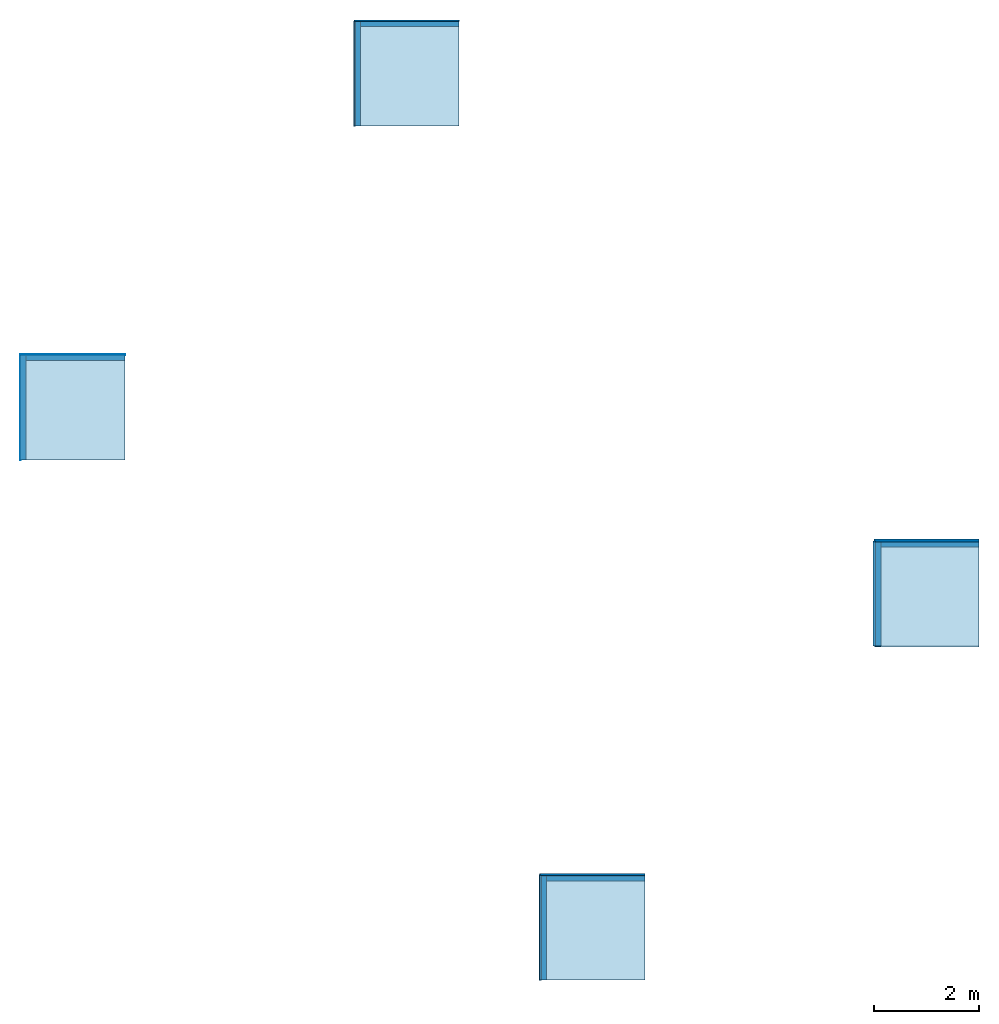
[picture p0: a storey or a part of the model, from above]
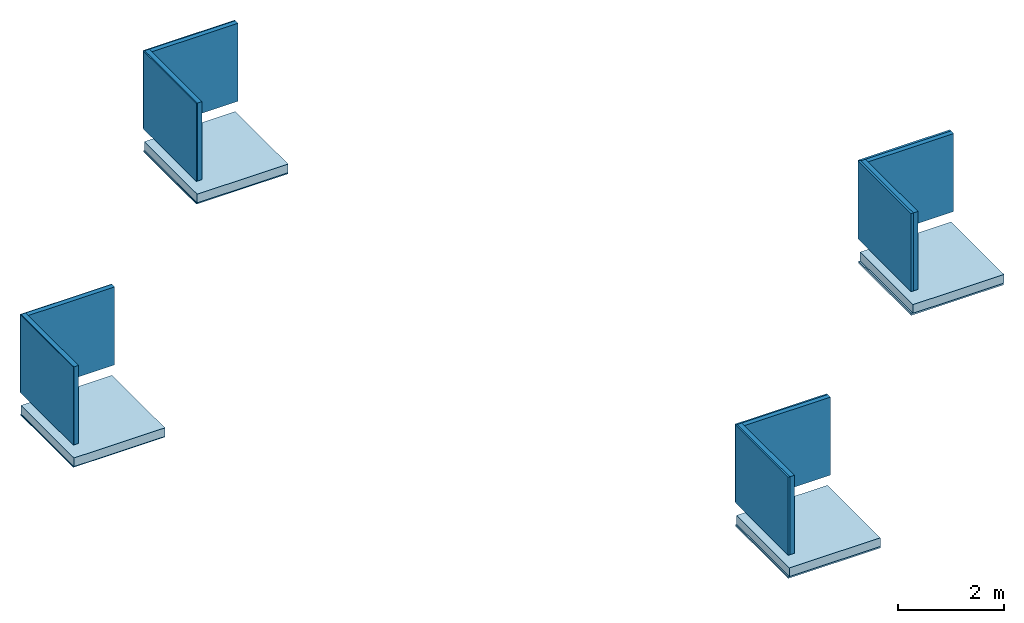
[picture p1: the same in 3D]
Properties of the parts of a building model (IFC2X3)

# File
Description: ViewDefinition [CoordinationView_V2.0, QuantityTakeOffAddOnView]
File name: 012345
Time: 2019-12-04T12:57:39
Written by: The EXPRESS Data Manager Version 5.02.0100.07 : 28 Aug 2013
Made in: 20190507_1515(x64) - Exporter 17.0.517.0 - Alternate UI 17.15.0.0
Comment: STEP Physical File produced by: The EXPRESS Data Manager Version 5.02.0100.07 : 28 Aug 2013 * Module: EDMstepFileFactory/EDMstandAlone * Creation date: Wed Dec 04 12:57:39 2019 * Host: lt-026 * Database: C:\Users\WF2BF~1.POE\AppData\Local\Temp\{160A05C8-261A-411D-A7B8-0925D6DDFBA5}\ifc * Database version: 5507 * Database creation date: Wed Dec 04 12:57:36 2019 * Schema: IFC2X3 * Model: DataRepository.ifc * Model creation date: Wed Dec 04 12:57:37 2019 * Header model: DataRepository.ifc_HeaderModel * Header model creation date: Wed Dec 04 12:57:37 2019 * EDMuser: sdai-user * EDMgroup: sdai-group * License ID and type: 5605 : Permanent license. Expiry date: * EDMstepFileFactory options: 020000

# IfcProject, 012345
LongName: Cadix Project Naam; Phase: Cadix leeg V2.0

# IfcSite, Default
RefLatitude: 52, 3, 20, 225830; RefLongitude: 5, 6, 28, 692855; RefElevation: 0 mm
Identity Data - Author: Cadix; Organization Name: Cadix
Other - Category: Project Information; Client Name: Vragen? info@cadix.nl; Project Address: Ampèrelaan 1c, 9207 AM Drachten; Project Issue Date: 06-06-2017; Project Name: Cadix Project Naam; Project Number: 012345; Project Status: Cadix leeg V2.0

# IfcBuilding
Pset_BuildingCommon - NumberOfStoreys: 2
Identity Data - Author: Cadix; Organization Name: Cadix
Other - Category: Project Information; Client Name: Vragen? info@cadix.nl; Project Address: Ampèrelaan 1c, 9207 AM Drachten; Project Issue Date: 06-06-2017; Project Name: Cadix Project Naam; Project Number: 012345; Project Status: Cadix leeg V2.0

# IfcBuildingStorey (2)
Dimensions - Computation Height: 0 mm
Identity Data - Structural: no; Building Story: yes; Type Name: niveau
Other - Category: Levels; Family: Level: niveau; Family and Type: Level: niveau; Type: Level: niveau; Type Id: Level: niveau; Family Name: Level
Constraints - Elevation Base: Project Base Point
Graphics - Color: 8421504; Line Pattern: 00_niveau; Line Weight: 1; Symbol: NLRS_00_LAB_niveau bovenkant_gen_cadix: 1.8mm; Symbol at End 1 Default: yes; Symbol at End 2 Default: no
Name | LongName = Name | Elevation (mm) | Constraints, Elevation (mm)
00 begane grond | 00 begane grond | -2.7707e-11 | 0
01 eerste verdieping | 01 eerste verdieping | 1800 | 1800

# IfcCovering: Compound Ceiling:NLRS_45_CEI_Heraklith - Basis 15x2000x600mm, Compound Ceiling:NLRS_45_CEI_Heraklith - Basis 15x2000x600mm:902306
In: 01 eerste verdieping
PredefinedType: CEILING; Classification: 45.0 (Uniformat); Material: Heraklith® | Basis - Houtwollaag - 2000x600mm 15 mm
Pset_CoveringCommon - Reference: NLRS_45_CEI_Heraklith - Basis 15x2000x600mm; Finish: Heraklith® | Basis - Houtwollaag - 2000x600mm;; TotalThickness: 15 mm
Pset_ManufacturerTypeInformation - Manufacturer: Knauf Insulation B.V.
BaseQuantities - GrossCeilingArea: 4 m2
Constraints - Height Offset From Level: -15 mm; Level: Level: 01 eerste verdieping; Room Bounding: yes
Dimensions - Area: 4 m2; Perimeter: 8000 mm; Volume: 0.06 m3
Other - Category: Ceilings; Family: Compound Ceiling: NLRS_45_CEI_Heraklith - Basis 15x2000x600mm; Family and Type: Compound Ceiling: NLRS_45_CEI_Heraklith - Basis 15x2000x600mm; Type: Compound Ceiling: NLRS_45_CEI_Heraklith - Basis 15x2000x600mm; Type Id: Compound Ceiling: NLRS_45_CEI_Heraklith - Basis 15x2000x600mm; Family Name: Compound Ceiling
Phasing - Phase Created: 1
Analytical Properties - Absorptance: 0.1; Heat Transfer Coefficient (U): 5.33333; Roughness: 1; Thermal mass: 675; Thermal Resistance (R): 0.1875
Construction - Thickness: 15 mm
Data - CE-codering: WW-EN 13168-L1-W1-T1-S1-P1-CS(10/Y)150/200-Cl1; Chloride gehalte: Cl1; Druksterkte kPa: 200; gewicht KG/M2: 8.5; kleur: Ongeverfd; pallet m2: 84 m2; panelen per pallet: 70; Randafwerking: Houtwol: Rechte kanten; Randafwerking: Isolatie: n.v.t.; Tolerantie: Breedte (W): (W1) +3/-3; Tolerantie: Dikte (T): (T1) +3/-2; Tolerantie: Haaksheid (S): (S1) ≤4; Tolerantie: Lengte (L): (L1) +5/-10; Tolerantie: Vlakheid (P): (P1) ≤6; vezelbreedte: 2mm
Graphics - Coarse Scale Fill Color: 0
Identity Data - Assembly Code: 45.0; brandweerstand: n.v.t; Description: Basispaneel - 15mm; DoP: W4302APCPR; email: customerservice.nl@knaufinsulation.com; geluidsabsorbtie: niet getest; Manufacturer: Knauf Insulation B.V.; Model: Heraklith® | Basispaneel is een houtwolcementpaneel; NLRS_C_Code_Brandklasse: B-s1,d0; NLRS_C_content_creator: Cadix; NLRS_C_content_versie: V1.0; phone: +31(0)162-421245; product URL: https://heraklith.nl/houtwol-producten/heraklith-basis; Type Image: Raster image: Heraklith Basispaneel.jpg; Type Name: NLRS_45_CEI_Heraklith - Basis 15x2000x600mm; URL: www.heraklith.nl; warmteweerstand: 0,15 (m2.K/W)

# IfcCovering: Compound Ceiling:NLRS_45_CEI_Heraklith - Basis 25x2000x600mm, Compound Ceiling:NLRS_45_CEI_Heraklith - Basis 25x2000x600mm:916327
In: 01 eerste verdieping
PredefinedType: CEILING; Classification: 45.0 (Uniformat); Material: Heraklith® | Basis - Houtwollaag - 2000x600mm 20 mm
Pset_CoveringCommon - Reference: NLRS_45_CEI_Heraklith - Basis 25x2000x600mm; Finish: Heraklith® | Basis - Houtwollaag - 2000x600mm;; TotalThickness: 20 mm
Pset_ManufacturerTypeInformation - Manufacturer: Knauf Insulation B.V.
BaseQuantities - GrossCeilingArea: 3.99 m2
Constraints - Room Bounding: yes; Height Offset From Level: -25 mm; Level: Level: 01 eerste verdieping
Dimensions - Area: 3.99 m2; Perimeter: 7990 mm; Volume: 0.0798 m3
Other - Category: Ceilings; Family: Compound Ceiling: NLRS_45_CEI_Heraklith - Basis 25x2000x600mm; Family and Type: Compound Ceiling: NLRS_45_CEI_Heraklith - Basis 25x2000x600mm; Type: Compound Ceiling: NLRS_45_CEI_Heraklith - Basis 25x2000x600mm; Type Id: Compound Ceiling: NLRS_45_CEI_Heraklith - Basis 25x2000x600mm; Family Name: Compound Ceiling
Phasing - Phase Created: 1
Analytical Properties - Roughness: 1; Absorptance: 0.1; Heat Transfer Coefficient (U): 4; Thermal mass: 900; Thermal Resistance (R): 0.25
Construction - Thickness: 20 mm
Data - CE-codering: WW-EN 13168-L1-W1-T1-S1-P1-CS(10/Y)150/200-Cl1; Chloride gehalte: Cl1; Druksterkte kPa: 200; gewicht KG/M2: 11.5; kleur: Ongeverfd; pallet m2: 48 m2; panelen per pallet: 40; Randafwerking: Houtwol: Rechte kanten; Randafwerking: Isolatie: n.v.t.; Tolerantie: Breedte (W): (W1) +3/-3; Tolerantie: Dikte (T): (T1) +3/-2; Tolerantie: Haaksheid (S): (S1) ≤4; Tolerantie: Lengte (L): (L1) +5/-10; Tolerantie: Vlakheid (P): (P1) ≤6; vezelbreedte: 2mm
Graphics - Coarse Scale Fill Color: 0
Identity Data - Type Image: Raster image: Heraklith Basispaneel.jpg; Assembly Code: 45.0; brandweerstand: n.v.t; Description: Basispaneel - 25mm; DoP: W4302APCPR; email: customerservice.nl@knaufinsulation.com; geluidsabsorbtie: max. 0,90; Manufacturer: Knauf Insulation B.V.; Model: Heraklith® | Basispaneel is een houtwolcementpaneel; NLRS_C_Code_Brandklasse: B-s1,d0; NLRS_C_content_creator: Cadix; NLRS_C_content_versie: V1.0; phone: +31(0)162-421245; product URL: https://heraklith.nl/houtwol-producten/heraklith-basis; Type Name: NLRS_45_CEI_Heraklith - Basis 25x2000x600mm; URL: www.heraklith.nl; warmteweerstand: 0,30 (m2.K/W)

# IfcCovering: Compound Ceiling:NLRS_45_CEI_Heraklith - Basis 35x2000x600mm, Compound Ceiling:NLRS_45_CEI_Heraklith - Basis 35x2000x600mm:918661
In: 01 eerste verdieping
PredefinedType: CEILING; Classification: 45.0 (Uniformat); Material: Heraklith® | Basis - Houtwollaag - 2000x600mm 35 mm
Pset_CoveringCommon - Reference: NLRS_45_CEI_Heraklith - Basis 35x2000x600mm; Finish: Heraklith® | Basis - Houtwollaag - 2000x600mm;; TotalThickness: 35 mm
Pset_ManufacturerTypeInformation - Manufacturer: Knauf Insulation B.V. Knauf Insulation B.V. Knauf Insulation B.V.
BaseQuantities - GrossCeilingArea: 3.98 m2
Constraints - Level: Level: 01 eerste verdieping; Room Bounding: yes; Height Offset From Level: -15 mm
Dimensions - Area: 3.98 m2; Perimeter: 7980 mm; Volume: 0.1393 m3
Other - Category: Ceilings; Family: Compound Ceiling: NLRS_45_CEI_Heraklith - Basis 35x2000x600mm; Family and Type: Compound Ceiling: NLRS_45_CEI_Heraklith - Basis 35x2000x600mm; Type: Compound Ceiling: NLRS_45_CEI_Heraklith - Basis 35x2000x600mm; Type Id: Compound Ceiling: NLRS_45_CEI_Heraklith - Basis 35x2000x600mm; Family Name: Compound Ceiling
Phasing - Phase Created: 1
Analytical Properties - Roughness: 1; Absorptance: 0.1; Heat Transfer Coefficient (U): 2.28571; Thermal mass: 1575; Thermal Resistance (R): 0.4375
Construction - Thickness: 35 mm
Data - CE-codering: WW-EN 13168-L1-W1-T1-S1-P1-CS(10/Y)150/200-Cl1; Chloride gehalte: Cl1; Druksterkte kPa: 150; gewicht KG/M2: 14.5; kleur: Ongeverfd; pallet m2: 34.8 m2; panelen per pallet: 29; Randafwerking: Houtwol: Rechte kanten; Randafwerking: Isolatie: n.v.t.; Tolerantie: Breedte (W): (W1) +3/-3; Tolerantie: Dikte (T): (T1) +3/-2; Tolerantie: Haaksheid (S): (S1) ≤4; Tolerantie: Lengte (L): (L1) +5/-10; Tolerantie: Vlakheid (P): (P1) ≤6; vezelbreedte: 2mm
Graphics - Coarse Scale Fill Color: 6724044
Identity Data - Type Image: Raster image: Heraklith Basispaneel.jpg; Assembly Code: 45.0; brandweerstand: n.v.t; Description: Basispaneel - 35mm; DoP: W4302APCPR; email: customerservice.nl@knaufinsulation.com; geluidsabsorbtie: 0,50; Manufacturer: Knauf Insulation B.V. Knauf Insulation B.V. Knauf Insulation B.V.; Model: Heraklith® | Basispaneel is een houtwolcementpaneel; NLRS_C_Code_Brandklasse: B-s1,d0; NLRS_C_content_creator: Cadix; NLRS_C_content_versie: V1.0; phone: +31(0)162-421245; product URL: https://heraklith.nl/houtwol-producten/heraklith-basis; Type Name: NLRS_45_CEI_Heraklith - Basis 35x2000x600mm; URL: www.heraklith.nl www.heraklith.nl; warmteweerstand: 0,40 (m2.K/W)

# IfcCovering: Compound Ceiling:NLRS_45_CEI_Heraklith - Basis 50x2000x600mm, Compound Ceiling:NLRS_45_CEI_Heraklith - Basis 50x2000x600mm:918680
In: 01 eerste verdieping
PredefinedType: CEILING; Classification: 45.0 (Uniformat); Material: Heraklith® | Basis - Houtwollaag - 2000x600mm 50 mm
Pset_CoveringCommon - Reference: NLRS_45_CEI_Heraklith - Basis 50x2000x600mm; Finish: Heraklith® | Basis - Houtwollaag - 2000x600mm;; TotalThickness: 50 mm
Pset_ManufacturerTypeInformation - Manufacturer: Knauf Insulation B.V.
BaseQuantities - GrossCeilingArea: 3.965 m2
Constraints - Level: Level: 01 eerste verdieping; Room Bounding: yes; Height Offset From Level: -25 mm
Dimensions - Area: 3.965 m2; Perimeter: 7965 mm; Volume: 0.19825 m3
Other - Category: Ceilings; Family: Compound Ceiling: NLRS_45_CEI_Heraklith - Basis 50x2000x600mm; Family and Type: Compound Ceiling: NLRS_45_CEI_Heraklith - Basis 50x2000x600mm; Type: Compound Ceiling: NLRS_45_CEI_Heraklith - Basis 50x2000x600mm; Type Id: Compound Ceiling: NLRS_45_CEI_Heraklith - Basis 50x2000x600mm; Family Name: Compound Ceiling
Phasing - Phase Created: 1
Analytical Properties - Roughness: 1; Absorptance: 0.1; Heat Transfer Coefficient (U): 1.6; Thermal mass: 2250; Thermal Resistance (R): 0.625
Construction - Thickness: 50 mm
Data - CE-codering: WW-EN 13168-L1-W1-T1-S1-P1-CS(10/Y)150/200-Cl1; Chloride gehalte: Cl1; Druksterkte kPa: 150; gewicht KG/M2: 19.5; kleur: Ongeverfd; pallet m2: 24 m2; panelen per pallet: 20; Randafwerking: Houtwol: Rechte kanten; Randafwerking: Isolatie: n.v.t.; Tolerantie: Breedte (W): (W1) +3/-3; Tolerantie: Dikte (T): (T1) +3/-2; Tolerantie: Haaksheid (S): (S1) ≤4; Tolerantie: Lengte (L): (L1) +5/-10; Tolerantie: Vlakheid (P): (P1) ≤6; vezelbreedte: 2mm
Graphics - Coarse Scale Fill Color: 0
Identity Data - Type Image: Raster image: Heraklith Basispaneel.jpg; Assembly Code: 45.0; brandweerstand: n.v.t; Description: Basispaneel - 50mm; DoP: W4302APCPR; email: customerservice.nl@knaufinsulation.com; geluidsabsorbtie: 0,65; Manufacturer: Knauf Insulation B.V.; Model: Heraklith® | Basispaneel is een houtwolcementpaneel; NLRS_C_Code_Brandklasse: B-s1,d0; NLRS_C_content_creator: Cadix; NLRS_C_content_versie: V1.0; phone: +31(0)162-421245; product URL: https://heraklith.nl/houtwol-producten/heraklith-basis; Type Name: NLRS_45_CEI_Heraklith - Basis 50x2000x600mm; URL: www.heraklith.nl; warmteweerstand: 0,60 (m2.K/W)

# IfcSlab: Floor:Generic 200mm (8)
PredefinedType: FLOOR; Material: Concrete, Precast Panels 200 mm
Pset_SlabCommon - IsExternal: no; LoadBearing: yes; PitchAngle: 0 deg; Reference: Generic 200mm; ThermalTransmittance: 5.23 kg/K/s3
BaseQuantities - Width: 200 mm
Constraints - Room Bounding: yes; Related to Mass: no
Dimensions - Thickness: 200 mm
Other - Category: Floors; Family: Floor: Generic 200mm; Family and Type: Floor: Generic 200mm; Type: Floor: Generic 200mm; Type Id: Floor: Generic 200mm; Family Name: Floor
Phasing - Phase Created: 1
Structural - Enable Analytical Model: no; Structural: no
Analytical Properties - Roughness: 3; Absorptance: 0.7; Heat Transfer Coefficient (U): 5.23; Thermal mass: 302220; Thermal Resistance (R): 0.191205
Construction - Function: Interior; Default Thickness: 200 mm
Graphics - Coarse Scale Fill Color: 0
Identity Data - Type Name: Generic 200mm
Materials and Finishes - Structural Material: Concrete, Precast Panels
Name (Floor:Generic 200mm:...) | In | GrossArea (m2) = Area (m2) | GrossVolume (m3) | BaseQuantities, Perimeter (mm) = Dimensions, Perimeter (mm) | Level | Height Offset From Level (mm) | Elevation at Bottom (mm) | Elevation at Top (mm) | Volume (m3)
921040 | 00 begane grond | 3.97 | 794 | 7970 | Level: 00 begane grond | -300 | -500 | -300 | 0.794
921108 | 00 begane grond | 3.97 | 794 | 7970 | Level: 00 begane grond | -300 | -500 | -300 | 0.794
921122 | 00 begane grond | 3.97 | 794 | 7970 | Level: 00 begane grond | -300 | -500 | -300 | 0.794
921136 | 00 begane grond | 3.97 | 794 | 7970 | Level: 00 begane grond | -300 | -500 | -300 | 0.794
921156 | 01 eerste verdieping | 4 | 800 | 8000 | Level: 01 eerste verdieping | 200 | 1800 | 2000 | 0.8
921201 | 01 eerste verdieping | 4 | 800 | 8000 | Level: 01 eerste verdieping | 195 | 1795 | 1995 | 0.8
921215 | 01 eerste verdieping | 4 | 800 | 8000 | Level: 01 eerste verdieping | 220 | 1820 | 2020 | 0.8
921229 | 01 eerste verdieping | 4 | 800 | 8000 | Level: 01 eerste verdieping | 225 | 1825 | 2025 | 0.8

# IfcSlab: Floor:NLRS_23_FL_Heraklith - Basis 15x2000x600mm, Floor:NLRS_23_FL_Heraklith - Basis 15x2000x600mm:902315
In: 00 begane grond
PredefinedType: FLOOR; Classification: 23.0 (Uniformat); Material: Heraklith® | Basis - Houtwollaag - 2000x600mm 15 mm
Pset_SlabCommon - IsExternal: yes; Reference: NLRS_23_FL_Heraklith - Basis 15x2000x600mm; LoadBearing: yes; ThermalTransmittance: 5.33333 kg/K/s3; PitchAngle: 0 deg
Pset_ManufacturerTypeInformation - Manufacturer: Knauf Insulation B.V.
BaseQuantities - GrossArea: 4 m2; GrossVolume: 60 m3; Perimeter: 8000 mm; Width: 15 mm
Constraints - Room Bounding: yes; Related to Mass: no; Height Offset From Level: -500 mm; Level: Level: 00 begane grond
Dimensions - Area: 4 m2; Elevation at Bottom: -515 mm; Elevation at Top: -500 mm; Perimeter: 8000 mm; Thickness: 15 mm; Volume: 0.06 m3
Other - Category: Floors; Family: Floor: NLRS_23_FL_Heraklith - Basis 15x2000x600mm; Family and Type: Floor: NLRS_23_FL_Heraklith - Basis 15x2000x600mm; Type: Floor: NLRS_23_FL_Heraklith - Basis 15x2000x600mm; Type Id: Floor: NLRS_23_FL_Heraklith - Basis 15x2000x600mm; Family Name: Floor
Phasing - Phase Created: 1
Structural - Enable Analytical Model: no; Structural: no
Analytical Properties - Roughness: 1; Absorptance: 0.1; Heat Transfer Coefficient (U): 5.33333; Thermal mass: 675; Thermal Resistance (R): 0.1875
Construction - Function: Exterior; Default Thickness: 15 mm
Data - gewicht KG/M2: 8.5; CE-codering: WW-EN 13168-L1-W1-T1-S1-P1-CS(10/Y)150/200-Cl1; Chloride gehalte: Cl1; Druksterkte kPa: 200; kleur: Ongeverfd; pallet m2: 84 m2; panelen per pallet: 70; Randafwerking: Houtwol: Rechte kanten; Randafwerking: Isolatie: n.v.t.; Tolerantie: Breedte (W): (W1) +3/-3; Tolerantie: Dikte (T): (T1) +3/-2; Tolerantie: Haaksheid (S): (S1) ≤4; Tolerantie: Lengte (L): (L1) +5/-10; Tolerantie: Vlakheid (P): (P1) ≤6; vezelbreedte: 2mm
Graphics - Coarse Scale Fill Color: 0
Identity Data - Type Image: Raster image: Heraklith Basispaneel.jpg; Assembly Code: 23.0; brandweerstand: n.v.t; Description: Basispaneel - 15mm; DoP: W4302APCPR; email: customerservice.nl@knaufinsulation.com; geluidsabsorbtie: niet getest; Manufacturer: Knauf Insulation B.V.; Model: Heraklith® | Basispaneel is een houtwolcementpaneel; NLRS_C_Code_Brandklasse: B-s1,d0; NLRS_C_content_creator: Cadix; NLRS_C_content_versie: V1.0; phone: +31(0)162-421245; product URL: https://heraklith.nl/houtwol-producten/heraklith-basis; Type Name: NLRS_23_FL_Heraklith - Basis 15x2000x600mm; URL: www.heraklith.nl; warmteweerstand: 0,15 (m2.K/W)

# IfcSlab: Floor:NLRS_23_FL_Heraklith - Basis 25x2000x600mm, Floor:NLRS_23_FL_Heraklith - Basis 25x2000x600mm:916336
In: 00 begane grond
PredefinedType: FLOOR; Classification: 23.0 (Uniformat); Material: Heraklith® | Basis - Houtwollaag - 2000x600mm 25 mm
Pset_SlabCommon - IsExternal: yes; LoadBearing: yes; PitchAngle: 0 deg; ThermalTransmittance: 3.2 kg/K/s3; Reference: NLRS_23_FL_Heraklith - Basis 25x2000x600mm
Pset_ManufacturerTypeInformation - Manufacturer: Knauf Insulation B.V.
BaseQuantities - GrossArea: 3.99997 m2; GrossVolume: 99.9994 m3; Perimeter: 8000 mm; Width: 25 mm
Constraints - Room Bounding: yes; Related to Mass: no; Level: Level: 00 begane grond; Height Offset From Level: -500 mm
Dimensions - Area: 3.99997 m2; Elevation at Bottom: -525 mm; Elevation at Top: -500 mm; Perimeter: 8000 mm; Thickness: 25 mm; Volume: 0.0999994 m3
Other - Category: Floors; Family: Floor: NLRS_23_FL_Heraklith - Basis 25x2000x600mm; Family and Type: Floor: NLRS_23_FL_Heraklith - Basis 25x2000x600mm; Type: Floor: NLRS_23_FL_Heraklith - Basis 25x2000x600mm; Type Id: Floor: NLRS_23_FL_Heraklith - Basis 25x2000x600mm; Family Name: Floor
Phasing - Phase Created: 1
Structural - Enable Analytical Model: no; Structural: no
Analytical Properties - Roughness: 1; Absorptance: 0.1; Heat Transfer Coefficient (U): 3.2; Thermal mass: 1125; Thermal Resistance (R): 0.3125
Construction - Function: Exterior; Default Thickness: 25 mm
Data - CE-codering: WW-EN 13168-L1-W1-T1-S1-P1-CS(10/Y)150/200-Cl1; Chloride gehalte: Cl1; Druksterkte kPa: 200; gewicht KG/M2: 11.5; kleur: Ongeverfd; pallet m2: 48 m2; panelen per pallet: 40; Randafwerking: Houtwol: Rechte kanten; Randafwerking: Isolatie: n.v.t.; Tolerantie: Breedte (W): (W1) +3/-3; Tolerantie: Dikte (T): (T1) +3/-2; Tolerantie: Haaksheid (S): (S1) ≤4; Tolerantie: Lengte (L): (L1) +5/-10; Tolerantie: Vlakheid (P): (P1) ≤6; vezelbreedte: 2mm
Graphics - Coarse Scale Fill Color: 0
Identity Data - Type Image: Raster image: Heraklith Basispaneel.jpg; Assembly Code: 23.0; brandweerstand: n.v.t; Description: Basispaneel - 25mm; DoP: W4302APCPR; email: customerservice.nl@knaufinsulation.com; geluidsabsorbtie: max. 0,90; Manufacturer: Knauf Insulation B.V.; Model: Heraklith® | Basispaneel is een houtwolcementpaneel; NLRS_C_Code_Brandklasse: B-s1,d0; NLRS_C_content_creator: Cadix; NLRS_C_content_versie: V1.0; phone: +31(0)162-421245; product URL: https://heraklith.nl/houtwol-producten/heraklith-basis; Type Name: NLRS_23_FL_Heraklith - Basis 25x2000x600mm; URL: www.heraklith.nl; warmteweerstand: 0,30 (m2.K/W)

# IfcSlab: Floor:NLRS_23_FL_Heraklith - Basis 35x2000x600mm, Floor:NLRS_23_FL_Heraklith - Basis 35x2000x600mm:918670
In: 00 begane grond
PredefinedType: FLOOR; Classification: 23.0 (Uniformat); Material: Heraklith® | Basis - Houtwollaag - 2000x600mm 35 mm
Pset_SlabCommon - IsExternal: yes; LoadBearing: yes; PitchAngle: 0 deg; Reference: NLRS_23_FL_Heraklith - Basis 35x2000x600mm; ThermalTransmittance: 2.28571 kg/K/s3
Pset_ManufacturerTypeInformation - Manufacturer: Knauf Insulation B.V.
BaseQuantities - GrossArea: 3.9999 m2; GrossVolume: 139.996 m3; Perimeter: 8000 mm; Width: 35 mm
Constraints - Room Bounding: yes; Related to Mass: no; Height Offset From Level: -500 mm; Level: Level: 00 begane grond
Dimensions - Area: 3.9999 m2; Elevation at Bottom: -535 mm; Elevation at Top: -500 mm; Perimeter: 8000 mm; Thickness: 35 mm; Volume: 0.139996 m3
Other - Category: Floors; Family: Floor: NLRS_23_FL_Heraklith - Basis 35x2000x600mm; Family and Type: Floor: NLRS_23_FL_Heraklith - Basis 35x2000x600mm; Type: Floor: NLRS_23_FL_Heraklith - Basis 35x2000x600mm; Type Id: Floor: NLRS_23_FL_Heraklith - Basis 35x2000x600mm; Family Name: Floor
Phasing - Phase Created: 1
Structural - Enable Analytical Model: no; Structural: no
Analytical Properties - Roughness: 1; Absorptance: 0.1; Heat Transfer Coefficient (U): 2.28571; Thermal mass: 1575; Thermal Resistance (R): 0.4375
Construction - Function: Exterior; Default Thickness: 35 mm
Data - CE-codering: WW-EN 13168-L1-W1-T1-S1-P1-CS(10/Y)150/200-Cl1; Chloride gehalte: Cl1; Druksterkte kPa: 150; gewicht KG/M2: 14.5; kleur: Ongeverfd; pallet m2: 34.8 m2; panelen per pallet: 29; Randafwerking: Houtwol: Rechte kanten; Randafwerking: Isolatie: n.v.t.; Tolerantie: Breedte (W): (W1) +3/-3; Tolerantie: Dikte (T): (T1) +3/-2; Tolerantie: Haaksheid (S): (S1) ≤4; Tolerantie: Lengte (L): (L1) +5/-10; Tolerantie: Vlakheid (P): (P1) ≤6; vezelbreedte: 2mm
Graphics - Coarse Scale Fill Color: 0
Identity Data - Type Image: Raster image: Heraklith Basispaneel.jpg; Assembly Code: 23.0; brandweerstand: n.v.t; Description: Basispaneel - 35mm; DoP: W4302APCPR; email: customerservice.nl@knaufinsulation.com; geluidsabsorbtie: 0,50; Manufacturer: Knauf Insulation B.V.; Model: Heraklith® | Basispaneel is een houtwolcementpaneel; NLRS_C_Code_Brandklasse: B-s1,d0; NLRS_C_content_creator: Cadix; NLRS_C_content_versie: V1.0; phone: +31(0)162-421245; product URL: https://heraklith.nl/houtwol-producten/heraklith-basis; Type Name: NLRS_23_FL_Heraklith - Basis 35x2000x600mm; URL: www.heraklith.nl; warmteweerstand: 0,40 (m2.K/W)

# IfcSlab: Floor:NLRS_23_FL_Heraklith - Basis 50x2000x600mm, Floor:NLRS_23_FL_Heraklith - Basis 50x2000x600mm:918689
In: 00 begane grond
PredefinedType: FLOOR; Classification: 23.0 (Uniformat); Material: Heraklith® | Basis - Houtwollaag - 2000x600mm 50 mm
Pset_SlabCommon - IsExternal: yes; LoadBearing: yes; PitchAngle: 0 deg; ThermalTransmittance: 1.6 kg/K/s3; Reference: NLRS_23_FL_Heraklith - Basis 50x2000x600mm
Pset_ManufacturerTypeInformation - Manufacturer: Knauf Insulation B.V.
BaseQuantities - GrossArea: 3.99969 m2; GrossVolume: 199.985 m3; Perimeter: 8000 mm; Width: 50 mm
Constraints - Room Bounding: yes; Related to Mass: no; Level: Level: 00 begane grond; Height Offset From Level: -500 mm
Dimensions - Area: 3.99969 m2; Elevation at Bottom: -550 mm; Elevation at Top: -500 mm; Perimeter: 8000 mm; Thickness: 50 mm; Volume: 0.199985 m3
Other - Category: Floors; Family: Floor: NLRS_23_FL_Heraklith - Basis 50x2000x600mm; Family and Type: Floor: NLRS_23_FL_Heraklith - Basis 50x2000x600mm; Type: Floor: NLRS_23_FL_Heraklith - Basis 50x2000x600mm; Type Id: Floor: NLRS_23_FL_Heraklith - Basis 50x2000x600mm; Family Name: Floor
Phasing - Phase Created: 1
Structural - Enable Analytical Model: no; Structural: no
Analytical Properties - Roughness: 1; Absorptance: 0.1; Heat Transfer Coefficient (U): 1.6; Thermal mass: 2250; Thermal Resistance (R): 0.625
Construction - Function: Exterior; Default Thickness: 50 mm
Data - CE-codering: WW-EN 13168-L1-W1-T1-S1-P1-CS(10/Y)150/200-Cl1; Chloride gehalte: Cl1; Druksterkte kPa: 150; gewicht KG/M2: 19.5; kleur: Ongeverfd; pallet m2: 24 m2; panelen per pallet: 20; Randafwerking: Houtwol: Rechte kanten; Randafwerking: Isolatie: n.v.t.; Tolerantie: Breedte (W): (W1) +3/-3; Tolerantie: Dikte (T): (T1) +3/-2; Tolerantie: Haaksheid (S): (S1) ≤4; Tolerantie: Lengte (L): (L1) +5/-10; Tolerantie: Vlakheid (P): (P1) ≤6; vezelbreedte: 2mm
Graphics - Coarse Scale Fill Color: 0
Identity Data - Type Image: Raster image: Heraklith Basispaneel.jpg; Assembly Code: 23.0; brandweerstand: n.v.t; Description: Basispaneel - 50mm; DoP: W4302APCPR; email: customerservice.nl@knaufinsulation.com; geluidsabsorbtie: 0,65; Manufacturer: Knauf Insulation B.V.; Model: Heraklith® | Basispaneel is een houtwolcementpaneel; NLRS_C_Code_Brandklasse: B-s1,d0; NLRS_C_content_creator: Cadix; NLRS_C_content_versie: V1.0; phone: +31(0)162-421245; product URL: https://heraklith.nl/houtwol-producten/heraklith-basis; Type Name: NLRS_23_FL_Heraklith - Basis 50x2000x600mm; URL: www.heraklith.nl; warmteweerstand: 0,60 (m2.K/W)

# IfcWallStandardCase: Basic Wall:Generic_100mm (8)
In: 00 begane grond
Type - PredefinedType: STANDARD; Material: Concrete, Precast Panels 100 mm
Type - Analytical Properties - Absorptance: 0.7; Heat Transfer Coefficient (U): 10.46; Roughness: 3; Thermal mass: 151110; Thermal Resistance (R): 0.0956023
Type - Construction - Wrapping at Inserts: Do not wrap; Function: Exterior; Width: 100 mm
Type - Graphics - Coarse Scale Fill Color: 0
Type - Identity Data - Type Name: Generic_100mm
Type - Materials and Finishes - Structural Material: Concrete, Precast Panels
Type - Other - Category: Walls; Family Name: Basic Wall
BaseQuantities - Height: 1800 mm; Width: 100 mm
Constraints - Room Bounding: yes; Base Constraint: Level: 00 begane grond; Base Extension Distance: 0 mm; Base is Attached: no; Base Offset: 0 mm; Related to Mass: no; Top Constraint: Level: 01 eerste verdieping; Top Extension Distance: 0 mm; Top is Attached: no; Top Offset: 0 mm; Location Line: Core Face: Exterior; Unconnected Height: 1800 mm
Other - Family: Basic Wall: Generic_100mm; Family and Type: Basic Wall: Generic_100mm; Type: Basic Wall: Generic_100mm; Type Id: Basic Wall: Generic_100mm
Phasing - Phase Created: 1
Structural - Enable Analytical Model: no; Structural: no; Structural Usage: Non-bearing
Pset_WallCommon - LoadBearing: no; ExtendToStructure: no; IsExternal: yes; Reference: Generic_100mm; ThermalTransmittance: 10.46 kg/K/s3
Name (Basic Wall:Generic_100mm:...) | BaseQuantities, Length (mm) | GrossFootprintArea (m2) | GrossSideArea (m2) = Area (m2) | GrossVolume (m3) = Volume (m3) | Dimensions, Length (mm)
920093 | 2000 | 0.2 | 3.6 | 0.36 | 1950
920188 | 1885 | 0.1885 | 3.393 | 0.3393 | 1935
920352 | 1995 | 0.1995 | 3.591 | 0.3591 | 1945
920500 | 1880 | 0.188 | 3.384 | 0.3384 | 1930
920594 | 1982.5 | 0.19825 | 3.5685 | 0.35685 | 1932.5
920699 | 1867.5 | 0.18675 | 3.3615 | 0.33615 | 1917.5
920843 | 1990 | 0.199 | 3.582 | 0.3582 | 1940
920934 | 1875 | 0.1875 | 3.375 | 0.3375 | 1925

# IfcWallStandardCase: Basic Wall:NLRS_41_WA_Heraklith - Basis 15x2000x600mm, Basic Wall:NLRS_41_WA_Heraklith - Basis 15x2000x600mm:902312
In: 00 begane grond
Type - PredefinedType: STANDARD; Material: Heraklith® | Basis - Houtwollaag - 2000x600mm 15 mm
Type - Analytical Properties - Roughness: 1; Absorptance: 0.1; Heat Transfer Coefficient (U): 5.33333; Thermal mass: 675; Thermal Resistance (R): 0.1875
Type - Construction - Wrapping at Inserts: Do not wrap; Function: Exterior; Width: 15 mm
Type - Data - gewicht KG/M2: 8.5; CE-codering: WW-EN 13168-L1-W1-T1-S1-P1-CS(10/Y)150/200-Cl1; Chloride gehalte: Cl1; Druksterkte kPa: 200; kleur: Ongeverfd; pallet m2: 84 m2; panelen per pallet: 70; Randafwerking: Houtwol: Rechte kanten; Randafwerking: Isolatie: n.v.t.; Tolerantie: Breedte (W): (W1) +3/-3; Tolerantie: Dikte (T): (T1) +3/-2; Tolerantie: Haaksheid (S): (S1) ≤4; Tolerantie: Lengte (L): (L1) +5/-10; Tolerantie: Vlakheid (P): (P1) ≤6; vezelbreedte: 2mm
Type - Graphics - Coarse Scale Fill Color: 0; Coarse Scale Fill Pattern: Solid fill
Type - Identity Data - Type Image: Raster image: Heraklith Basispaneel.jpg; Assembly Code: 41.10; Assembly Description: buitenwandafwerkingen; algemeen (verzamelniveau); brandweerstand: n.v.t; Description: Basispaneel - 15mm; DoP: W4302APCPR; email: customerservice.nl@knaufinsulation.com; geluidsabsorbtie: niet getest; Manufacturer: Knauf Insulation B.V.; Model: Heraklith® | Basispaneel is een houtwolcementpaneel; NLRS_C_Code_Brandklasse: B-s1,d0; NLRS_C_content_creator: Cadix; NLRS_C_content_versie: V1.0; phone: +31(0)162-421245; product URL: https://heraklith.nl/houtwol-producten/heraklith-basis; Type Name: NLRS_41_WA_Heraklith - Basis 15x2000x600mm; URL: www.heraklith.nl; warmteweerstand: 0,15 (m2.K/W)
Type - Other - Category: Walls; Family Name: Basic Wall
Classification: 41.10 buitenwandafwerkingen; algemeen (verzamelniveau) (Uniformat)
BaseQuantities - Height: 1800 mm; Length: 2000 mm; Width: 15 mm; GrossFootprintArea: 0.03 m2; GrossSideArea: 3.6 m2; GrossVolume: 0.054 m3
Constraints - Room Bounding: yes; Base Constraint: Level: 00 begane grond; Base Extension Distance: 0 mm; Base is Attached: no; Base Offset: 0 mm; Location Line: Wall Centerline; Related to Mass: no; Top Constraint: Level: 01 eerste verdieping; Top Extension Distance: 0 mm; Top is Attached: no; Top Offset: 0 mm; Unconnected Height: 1800 mm
Dimensions - Area: 3.6 m2; Length: 2000 mm; Volume: 0.054 m3
Other - Family: Basic Wall: NLRS_41_WA_Heraklith - Basis 15x2000x600mm; Family and Type: Basic Wall: NLRS_41_WA_Heraklith - Basis 15x2000x600mm; Type: Basic Wall: NLRS_41_WA_Heraklith - Basis 15x2000x600mm; Type Id: Basic Wall: NLRS_41_WA_Heraklith - Basis 15x2000x600mm
Phasing - Phase Created: 1
Structural - Enable Analytical Model: no; Structural: no; Structural Usage: Non-bearing
Pset_WallCommon - LoadBearing: no; ExtendToStructure: no; Reference: NLRS_41_WA_Heraklith - Basis 15x2000x600mm; IsExternal: yes; ThermalTransmittance: 5.33333 kg/K/s3
Pset_ManufacturerTypeInformation - Manufacturer: Knauf Insulation B.V.

# IfcWallStandardCase: Basic Wall:NLRS_41_WA_Heraklith - Basis 25x2000x600mm, Basic Wall:NLRS_41_WA_Heraklith - Basis 25x2000x600mm:916333
In: 00 begane grond
Type - PredefinedType: STANDARD; Material: Heraklith® | Basis - Houtwollaag - 2000x600mm 25 mm
Type - Analytical Properties - Roughness: 1; Absorptance: 0.1; Heat Transfer Coefficient (U): 3.2; Thermal mass: 1125; Thermal Resistance (R): 0.3125
Type - Construction - Wrapping at Inserts: Do not wrap; Function: Exterior; Width: 25 mm
Type - Data - CE-codering: WW-EN 13168-L1-W1-T1-S1-P1-CS(10/Y)150/200-Cl1; Chloride gehalte: Cl1; Druksterkte kPa: 200; gewicht KG/M2: 11.5; kleur: Ongeverfd; pallet m2: 48 m2; panelen per pallet: 40; Randafwerking: Houtwol: Rechte kanten; Randafwerking: Isolatie: n.v.t.; Tolerantie: Breedte (W): (W1) +3/-3; Tolerantie: Dikte (T): (T1) +3/-2; Tolerantie: Haaksheid (S): (S1) ≤4; Tolerantie: Lengte (L): (L1) +5/-10; Tolerantie: Vlakheid (P): (P1) ≤6; vezelbreedte: 2mm
Type - Graphics - Coarse Scale Fill Color: 0; Coarse Scale Fill Pattern: Solid fill
Type - Identity Data - Type Image: Raster image: Heraklith Basispaneel.jpg; Assembly Code: 41.10; Assembly Description: buitenwandafwerkingen; algemeen (verzamelniveau); brandweerstand: n.v.t; Description: Basispaneel - 25mm; DoP: W4302APCPR; email: customerservice.nl@knaufinsulation.com; geluidsabsorbtie: max. 0,90; Manufacturer: Knauf Insulation B.V.; Model: Heraklith® | Basispaneel is een houtwolcementpaneel; NLRS_C_Code_Brandklasse: B-s1,d0; NLRS_C_content_creator: Cadix; NLRS_C_content_versie: V1.0; phone: +31(0)162-421245; product URL: https://heraklith.nl/houtwol-producten/heraklith-basis; Type Name: NLRS_41_WA_Heraklith - Basis 25x2000x600mm; URL: www.heraklith.nl; warmteweerstand: 0,30 (m2.K/W)
Type - Other - Category: Walls; Family Name: Basic Wall
Classification: 41.10 buitenwandafwerkingen; algemeen (verzamelniveau) (Uniformat)
BaseQuantities - Height: 1800 mm; Length: 2000 mm; Width: 25 mm; GrossFootprintArea: 0.05 m2; GrossSideArea: 3.6 m2; GrossVolume: 0.09 m3
Constraints - Room Bounding: yes; Base Constraint: Level: 00 begane grond; Base Extension Distance: 0 mm; Base is Attached: no; Base Offset: 0 mm; Location Line: Wall Centerline; Related to Mass: no; Top Constraint: Level: 01 eerste verdieping; Top Extension Distance: 0 mm; Top is Attached: no; Top Offset: 0 mm; Unconnected Height: 1800 mm
Dimensions - Area: 3.6 m2; Length: 2000 mm; Volume: 0.09 m3
Other - Family: Basic Wall: NLRS_41_WA_Heraklith - Basis 25x2000x600mm; Family and Type: Basic Wall: NLRS_41_WA_Heraklith - Basis 25x2000x600mm; Type: Basic Wall: NLRS_41_WA_Heraklith - Basis 25x2000x600mm; Type Id: Basic Wall: NLRS_41_WA_Heraklith - Basis 25x2000x600mm
Phasing - Phase Created: 1
Structural - Enable Analytical Model: no; Structural: no; Structural Usage: Non-bearing
Pset_WallCommon - LoadBearing: no; ExtendToStructure: no; IsExternal: yes; ThermalTransmittance: 3.2 kg/K/s3; Reference: NLRS_41_WA_Heraklith - Basis 25x2000x600mm
Pset_ManufacturerTypeInformation - Manufacturer: Knauf Insulation B.V.

# IfcWallStandardCase: Basic Wall:NLRS_41_WA_Heraklith - Basis 35x2000x600mm, Basic Wall:NLRS_41_WA_Heraklith - Basis 35x2000x600mm:918667
In: 00 begane grond
Type - PredefinedType: STANDARD; Material: Heraklith® | Basis - Houtwollaag - 2000x600mm 35 mm
Type - Analytical Properties - Roughness: 1; Absorptance: 0.1; Heat Transfer Coefficient (U): 2.28571; Thermal mass: 1575; Thermal Resistance (R): 0.4375
Type - Construction - Wrapping at Inserts: Do not wrap; Function: Exterior; Width: 35 mm
Type - Data - CE-codering: WW-EN 13168-L1-W1-T1-S1-P1-CS(10/Y)150/200-Cl1; Chloride gehalte: Cl1; Druksterkte kPa: 150; gewicht KG/M2: 14.5; kleur: Ongeverfd; pallet m2: 34.8 m2; panelen per pallet: 29; Randafwerking: Houtwol: Rechte kanten; Randafwerking: Isolatie: n.v.t.; Tolerantie: Breedte (W): (W1) +3/-3; Tolerantie: Dikte (T): (T1) +3/-2; Tolerantie: Haaksheid (S): (S1) ≤4; Tolerantie: Lengte (L): (L1) +5/-10; Tolerantie: Vlakheid (P): (P1) ≤6; vezelbreedte: 2mm
Type - Graphics - Coarse Scale Fill Color: 0; Coarse Scale Fill Pattern: Solid fill
Type - Identity Data - Type Image: Raster image: Heraklith Basispaneel.jpg; Assembly Code: 41.10; Assembly Description: buitenwandafwerkingen; algemeen (verzamelniveau); brandweerstand: n.v.t; Description: Basispaneel - 35mm; DoP: W4302APCPR; email: customerservice.nl@knaufinsulation.com; geluidsabsorbtie: 0,50; Manufacturer: Knauf Insulation B.V.; Model: Heraklith® | Basispaneel is een houtwolcementpaneel; NLRS_C_Code_Brandklasse: B-s1,d0; NLRS_C_content_creator: Cadix; NLRS_C_content_versie: V1.0; phone: +31(0)162-421245; product URL: https://heraklith.nl/houtwol-producten/heraklith-basis; Type Name: NLRS_41_WA_Heraklith - Basis 35x2000x600mm; URL: www.heraklith.nl; warmteweerstand: 0,40 (m2.K/W)
Type - Other - Category: Walls; Family Name: Basic Wall
Classification: 41.10 buitenwandafwerkingen; algemeen (verzamelniveau) (Uniformat)
BaseQuantities - Height: 1800 mm; Length: 2000 mm; Width: 35 mm; GrossFootprintArea: 0.07 m2; GrossSideArea: 3.6 m2; GrossVolume: 0.126 m3
Constraints - Room Bounding: yes; Base Constraint: Level: 00 begane grond; Base Extension Distance: 0 mm; Base is Attached: no; Base Offset: 0 mm; Location Line: Wall Centerline; Related to Mass: no; Top Constraint: Level: 01 eerste verdieping; Top Extension Distance: 0 mm; Top is Attached: no; Top Offset: 0 mm; Unconnected Height: 1800 mm
Dimensions - Area: 3.6 m2; Length: 2000 mm; Volume: 0.126 m3
Other - Family: Basic Wall: NLRS_41_WA_Heraklith - Basis 35x2000x600mm; Family and Type: Basic Wall: NLRS_41_WA_Heraklith - Basis 35x2000x600mm; Type: Basic Wall: NLRS_41_WA_Heraklith - Basis 35x2000x600mm; Type Id: Basic Wall: NLRS_41_WA_Heraklith - Basis 35x2000x600mm
Phasing - Phase Created: 1
Structural - Enable Analytical Model: no; Structural: no; Structural Usage: Non-bearing
Pset_WallCommon - LoadBearing: no; ExtendToStructure: no; IsExternal: yes; Reference: NLRS_41_WA_Heraklith - Basis 35x2000x600mm; ThermalTransmittance: 2.28571 kg/K/s3
Pset_ManufacturerTypeInformation - Manufacturer: Knauf Insulation B.V.

# IfcWallStandardCase: Basic Wall:NLRS_41_WA_Heraklith - Basis 50x2000x600mm, Basic Wall:NLRS_41_WA_Heraklith - Basis 50x2000x600mm:918686
In: 00 begane grond
Type - PredefinedType: STANDARD; Material: Heraklith® | Basis - Houtwollaag - 2000x600mm 50 mm
Type - Analytical Properties - Roughness: 1; Absorptance: 0.1; Heat Transfer Coefficient (U): 1.6; Thermal mass: 2250; Thermal Resistance (R): 0.625
Type - Construction - Wrapping at Inserts: Do not wrap; Function: Exterior; Width: 50 mm
Type - Data - CE-codering: WW-EN 13168-L1-W1-T1-S1-P1-CS(10/Y)150/200-Cl1; Chloride gehalte: Cl1; Druksterkte kPa: 150; gewicht KG/M2: 19.5; kleur: Ongeverfd; pallet m2: 24 m2; panelen per pallet: 20; Randafwerking: Houtwol: Rechte kanten; Randafwerking: Isolatie: n.v.t.; Tolerantie: Breedte (W): (W1) +3/-3; Tolerantie: Dikte (T): (T1) +3/-2; Tolerantie: Haaksheid (S): (S1) ≤4; Tolerantie: Lengte (L): (L1) +5/-10; Tolerantie: Vlakheid (P): (P1) ≤6; vezelbreedte: 2mm
Type - Graphics - Coarse Scale Fill Color: 0; Coarse Scale Fill Pattern: Solid fill
Type - Identity Data - Type Image: Raster image: Heraklith Basispaneel.jpg; Assembly Code: 41.10; Assembly Description: buitenwandafwerkingen; algemeen (verzamelniveau); brandweerstand: n.v.t; Description: Basispaneel - 50mm; DoP: W4302APCPR; email: customerservice.nl@knaufinsulation.com; geluidsabsorbtie: 0,65; Manufacturer: Knauf Insulation B.V.; Model: Heraklith® | Basispaneel is een houtwolcementpaneel; NLRS_C_Code_Brandklasse: B-s1,d0; NLRS_C_content_creator: Cadix; NLRS_C_content_versie: V1.0; phone: +31(0)162-421245; product URL: https://heraklith.nl/houtwol-producten/heraklith-basis; Type Name: NLRS_41_WA_Heraklith - Basis 50x2000x600mm; URL: www.heraklith.nl; warmteweerstand: 0,60 (m2.K/W)
Type - Other - Category: Walls; Family Name: Basic Wall
Classification: 41.10 buitenwandafwerkingen; algemeen (verzamelniveau) (Uniformat)
BaseQuantities - Height: 1800 mm; Length: 2000 mm; Width: 50 mm; GrossFootprintArea: 0.1 m2; GrossSideArea: 3.6 m2; GrossVolume: 0.18 m3
Constraints - Room Bounding: yes; Base Constraint: Level: 00 begane grond; Base Extension Distance: 0 mm; Base is Attached: no; Base Offset: 0 mm; Location Line: Wall Centerline; Related to Mass: no; Top Constraint: Level: 01 eerste verdieping; Top Extension Distance: 0 mm; Top is Attached: no; Top Offset: 0 mm; Unconnected Height: 1800 mm
Dimensions - Area: 3.6 m2; Length: 2000 mm; Volume: 0.18 m3
Other - Family: Basic Wall: NLRS_41_WA_Heraklith - Basis 50x2000x600mm; Family and Type: Basic Wall: NLRS_41_WA_Heraklith - Basis 50x2000x600mm; Type: Basic Wall: NLRS_41_WA_Heraklith - Basis 50x2000x600mm; Type Id: Basic Wall: NLRS_41_WA_Heraklith - Basis 50x2000x600mm
Phasing - Phase Created: 1
Structural - Enable Analytical Model: no; Structural: no; Structural Usage: Non-bearing
Pset_WallCommon - LoadBearing: no; ExtendToStructure: no; IsExternal: yes; ThermalTransmittance: 1.6 kg/K/s3; Reference: NLRS_41_WA_Heraklith - Basis 50x2000x600mm
Pset_ManufacturerTypeInformation - Manufacturer: Knauf Insulation B.V.

# IfcWallStandardCase: Basic Wall:NLRS_42_WA_Heraklith - Basis 15x2000x600mm, Basic Wall:NLRS_42_WA_Heraklith - Basis 15x2000x600mm:902311
In: 00 begane grond
Type - PredefinedType: STANDARD; Material: Heraklith® | Basis - Houtwollaag - 2000x600mm 15 mm
Type - Analytical Properties - Roughness: 1; Absorptance: 0.1; Heat Transfer Coefficient (U): 5.33333; Thermal mass: 675; Thermal Resistance (R): 0.1875
Type - Construction - Function: Interior; Width: 15 mm; Wrapping at Inserts: Do not wrap
Type - Data - gewicht KG/M2: 8.5; CE-codering: WW-EN 13168-L1-W1-T1-S1-P1-CS(10/Y)150/200-Cl1; Chloride gehalte: Cl1; Druksterkte kPa: 200; kleur: Ongeverfd; pallet m2: 84 m2; panelen per pallet: 70; Randafwerking: Houtwol: Rechte kanten; Randafwerking: Isolatie: n.v.t.; Tolerantie: Breedte (W): (W1) +3/-3; Tolerantie: Dikte (T): (T1) +3/-2; Tolerantie: Haaksheid (S): (S1) ≤4; Tolerantie: Lengte (L): (L1) +5/-10; Tolerantie: Vlakheid (P): (P1) ≤6; vezelbreedte: 2mm
Type - Graphics - Coarse Scale Fill Color: 0; Coarse Scale Fill Pattern: Solid fill
Type - Identity Data - Type Image: Raster image: Heraklith Basispaneel.jpg; Assembly Code: 42.10; Assembly Description: binnenwandafwerkingen; algemeen (verzamelniveau); brandweerstand: n.v.t; Description: Basispaneel - 15mm; DoP: W4302APCPR; email: customerservice.nl@knaufinsulation.com; geluidsabsorbtie: niet getest; Manufacturer: Knauf Insulation B.V. Knauf Insulation B.V.; Model: Heraklith® | Basispaneel is een houtwolcementpaneel; NLRS_C_Code_Brandklasse: B-s1,d0; NLRS_C_content_creator: Cadix; NLRS_C_content_versie: V1.0; phone: +31(0)162-421245; product URL: https://heraklith.nl/houtwol-producten/heraklith-basis; Type Name: NLRS_42_WA_Heraklith - Basis 15x2000x600mm; URL: www.heraklith.nl; warmteweerstand: 0,15 (m2.K/W)
Type - Other - Category: Walls; Family Name: Basic Wall
Classification: 42.10 binnenwandafwerkingen; algemeen (verzamelniveau) (Uniformat)
BaseQuantities - Height: 1800 mm; Length: 2000 mm; Width: 15 mm; GrossFootprintArea: 0.03 m2; GrossSideArea: 3.6 m2; GrossVolume: 0.054 m3
Constraints - Room Bounding: yes; Base Constraint: Level: 00 begane grond; Base Extension Distance: 0 mm; Base is Attached: no; Base Offset: 0 mm; Location Line: Wall Centerline; Related to Mass: no; Top Constraint: Level: 01 eerste verdieping; Top Extension Distance: 0 mm; Top is Attached: no; Top Offset: 0 mm; Unconnected Height: 1800 mm
Dimensions - Area: 3.6 m2; Length: 2000 mm; Volume: 0.054 m3
Other - Family: Basic Wall: NLRS_42_WA_Heraklith - Basis 15x2000x600mm; Family and Type: Basic Wall: NLRS_42_WA_Heraklith - Basis 15x2000x600mm; Type: Basic Wall: NLRS_42_WA_Heraklith - Basis 15x2000x600mm; Type Id: Basic Wall: NLRS_42_WA_Heraklith - Basis 15x2000x600mm
Phasing - Phase Created: 1
Structural - Enable Analytical Model: no; Structural: no; Structural Usage: Non-bearing
Pset_WallCommon - Reference: NLRS_42_WA_Heraklith - Basis 15x2000x600mm; LoadBearing: no; ExtendToStructure: no; IsExternal: no; ThermalTransmittance: 5.33333 kg/K/s3
Pset_ManufacturerTypeInformation - Manufacturer: Knauf Insulation B.V. Knauf Insulation B.V.

# IfcWallStandardCase: Basic Wall:NLRS_42_WA_Heraklith - Basis 25x2000x600mm, Basic Wall:NLRS_42_WA_Heraklith - Basis 25x2000x600mm:916332
In: 00 begane grond
Type - PredefinedType: STANDARD; Material: Heraklith® | Basis - Houtwollaag - 2000x600mm 25 mm
Type - Analytical Properties - Roughness: 1; Absorptance: 0.1; Heat Transfer Coefficient (U): 3.2; Thermal mass: 1125; Thermal Resistance (R): 0.3125
Type - Construction - Function: Interior; Wrapping at Inserts: Do not wrap; Width: 25 mm
Type - Data - CE-codering: WW-EN 13168-L1-W1-T1-S1-P1-CS(10/Y)150/200-Cl1; Chloride gehalte: Cl1; Druksterkte kPa: 150; gewicht KG/M2: 11.5; kleur: Ongeverfd; pallet m2: 48 m2; panelen per pallet: 40; Randafwerking: Houtwol: Rechte kanten; Randafwerking: Isolatie: n.v.t.; Tolerantie: Breedte (W): (W1) +3/-3; Tolerantie: Dikte (T): (T1) +3/-2; Tolerantie: Haaksheid (S): (S1) ≤4; Tolerantie: Lengte (L): (L1) +5/-10; Tolerantie: Vlakheid (P): (P1) ≤6; vezelbreedte: 2mm
Type - Graphics - Coarse Scale Fill Color: 0; Coarse Scale Fill Pattern: Solid fill
Type - Identity Data - Type Image: Raster image: Heraklith Basispaneel.jpg; Assembly Code: 42.10; Assembly Description: binnenwandafwerkingen; algemeen (verzamelniveau); brandweerstand: n.v.t; Description: Basispaneel - 25mm; DoP: W4302APCPR; email: customerservice.nl@knaufinsulation.com; geluidsabsorbtie: max. 0,90; Manufacturer: Knauf Insulation B.V. Knauf Insulation B.V.; Model: Heraklith® | Basispaneel is een houtwolcementpaneel; NLRS_C_Code_Brandklasse: B-s1,d0; NLRS_C_content_creator: Cadix; NLRS_C_content_versie: V1.0; phone: +31(0)162-421245 +31(0)162-421245; product URL: https://heraklith.nl/houtwol-producten/heraklith-basis https://heraklith.nl/houtwol-producten/heraklith-basis https://heraklith.nl/houtwol-producten/heraklith-basis; Type Name: NLRS_42_WA_Heraklith - Basis 25x2000x600mm; URL: www.heraklith.nl; warmteweerstand: 0,30 (m2.K/W)
Type - Other - Category: Walls; Family Name: Basic Wall
Classification: 42.10 binnenwandafwerkingen; algemeen (verzamelniveau) (Uniformat)
BaseQuantities - Height: 1800 mm; Length: 2000 mm; Width: 25 mm; GrossFootprintArea: 0.05 m2; GrossSideArea: 3.6 m2; GrossVolume: 0.09 m3
Constraints - Room Bounding: yes; Base Constraint: Level: 00 begane grond; Base Extension Distance: 0 mm; Base is Attached: no; Base Offset: 0 mm; Location Line: Wall Centerline; Related to Mass: no; Top Constraint: Level: 01 eerste verdieping; Top Extension Distance: 0 mm; Top is Attached: no; Top Offset: 0 mm; Unconnected Height: 1800 mm
Dimensions - Area: 3.6 m2; Length: 2000 mm; Volume: 0.09 m3
Other - Family: Basic Wall: NLRS_42_WA_Heraklith - Basis 25x2000x600mm; Family and Type: Basic Wall: NLRS_42_WA_Heraklith - Basis 25x2000x600mm; Type: Basic Wall: NLRS_42_WA_Heraklith - Basis 25x2000x600mm; Type Id: Basic Wall: NLRS_42_WA_Heraklith - Basis 25x2000x600mm
Phasing - Phase Created: 1
Structural - Enable Analytical Model: no; Structural: no; Structural Usage: Non-bearing
Pset_WallCommon - LoadBearing: no; ExtendToStructure: no; IsExternal: no; Reference: NLRS_42_WA_Heraklith - Basis 25x2000x600mm; ThermalTransmittance: 3.2 kg/K/s3
Pset_ManufacturerTypeInformation - Manufacturer: Knauf Insulation B.V. Knauf Insulation B.V.

# IfcWallStandardCase: Basic Wall:NLRS_42_WA_Heraklith - Basis 35x2000x600mm, Basic Wall:NLRS_42_WA_Heraklith - Basis 35x2000x600mm:918666
In: 00 begane grond
Type - PredefinedType: STANDARD; Material: Heraklith® | Basis - Houtwollaag - 2000x600mm 35 mm
Type - Analytical Properties - Roughness: 1; Absorptance: 0.1; Heat Transfer Coefficient (U): 2.28571; Thermal mass: 1575; Thermal Resistance (R): 0.4375
Type - Construction - Function: Interior; Wrapping at Inserts: Do not wrap; Width: 35 mm
Type - Data - CE-codering: WW-EN 13168-L1-W1-T1-S1-P1-CS(10/Y)150/200-Cl1; Chloride gehalte: Cl1; Druksterkte kPa: 150; gewicht KG/M2: 14.5; kleur: Ongeverfd; pallet m2: 34.8 m2; panelen per pallet: 29; Randafwerking: Houtwol: Rechte kanten; Randafwerking: Isolatie: n.v.t.; Tolerantie: Breedte (W): (W1) +3/-3; Tolerantie: Dikte (T): (T1) +3/-2; Tolerantie: Haaksheid (S): (S1) ≤4; Tolerantie: Lengte (L): (L1) +5/-10; Tolerantie: Vlakheid (P): (P1) ≤6; vezelbreedte: 2mm
Type - Graphics - Coarse Scale Fill Color: 0; Coarse Scale Fill Pattern: Solid fill
Type - Identity Data - Type Image: Raster image: Heraklith Basispaneel.jpg; Assembly Code: 42.10; Assembly Description: binnenwandafwerkingen; algemeen (verzamelniveau); brandweerstand: n.v.t; Description: Basispaneel - 35mm; DoP: W4302APCPR; email: customerservice.nl@knaufinsulation.com; geluidsabsorbtie: 0,50; Manufacturer: Knauf Insulation B.V. Knauf Insulation B.V.; Model: Heraklith® | Basispaneel is een houtwolcementpaneel; NLRS_C_Code_Brandklasse: B-s1,d0; NLRS_C_content_creator: Cadix; NLRS_C_content_versie: V1.0; phone: +31(0)162-421245; product URL: https://heraklith.nl/houtwol-producten/heraklith-basis; Type Name: NLRS_42_WA_Heraklith - Basis 35x2000x600mm; URL: www.heraklith.nl; warmteweerstand: 0,40 (m2.K/W)
Type - Other - Category: Walls; Family Name: Basic Wall
Classification: 42.10 binnenwandafwerkingen; algemeen (verzamelniveau) (Uniformat)
BaseQuantities - Height: 1800 mm; Length: 2000 mm; Width: 35 mm; GrossFootprintArea: 0.07 m2; GrossSideArea: 3.6 m2; GrossVolume: 0.126 m3
Constraints - Room Bounding: yes; Base Constraint: Level: 00 begane grond; Base Extension Distance: 0 mm; Base is Attached: no; Base Offset: 0 mm; Location Line: Wall Centerline; Related to Mass: no; Top Constraint: Level: 01 eerste verdieping; Top Extension Distance: 0 mm; Top is Attached: no; Top Offset: 0 mm; Unconnected Height: 1800 mm
Dimensions - Area: 3.6 m2; Length: 2000 mm; Volume: 0.126 m3
Other - Family: Basic Wall: NLRS_42_WA_Heraklith - Basis 35x2000x600mm; Family and Type: Basic Wall: NLRS_42_WA_Heraklith - Basis 35x2000x600mm; Type: Basic Wall: NLRS_42_WA_Heraklith - Basis 35x2000x600mm; Type Id: Basic Wall: NLRS_42_WA_Heraklith - Basis 35x2000x600mm
Phasing - Phase Created: 1
Structural - Enable Analytical Model: no; Structural: no; Structural Usage: Non-bearing
Pset_WallCommon - LoadBearing: no; ExtendToStructure: no; IsExternal: no; Reference: NLRS_42_WA_Heraklith - Basis 35x2000x600mm; ThermalTransmittance: 2.28571 kg/K/s3
Pset_ManufacturerTypeInformation - Manufacturer: Knauf Insulation B.V. Knauf Insulation B.V.

# IfcWallStandardCase: Basic Wall:NLRS_42_WA_Heraklith - Basis 50x2000x600mm, Basic Wall:NLRS_42_WA_Heraklith - Basis 50x2000x600mm:918685
In: 00 begane grond
Type - PredefinedType: STANDARD; Material: Heraklith® | Basis - Houtwollaag - 2000x600mm 50 mm
Type - Analytical Properties - Roughness: 1; Absorptance: 0.1; Heat Transfer Coefficient (U): 1.6; Thermal mass: 2250; Thermal Resistance (R): 0.625
Type - Construction - Function: Interior; Wrapping at Inserts: Do not wrap; Width: 50 mm
Type - Data - CE-codering: WW-EN 13168-L1-W1-T1-S1-P1-CS(10/Y)150/200-Cl1; Chloride gehalte: Cl1; Druksterkte kPa: 200; gewicht KG/M2: 19.5; kleur: Ongeverfd; pallet m2: 24 m2; panelen per pallet: 20; Randafwerking: Houtwol: Rechte kanten; Randafwerking: Isolatie: n.v.t.; Tolerantie: Breedte (W): (W1) +3/-3; Tolerantie: Dikte (T): (T1) +3/-2; Tolerantie: Haaksheid (S): (S1) ≤4; Tolerantie: Lengte (L): (L1) +5/-10; Tolerantie: Vlakheid (P): (P1) ≤6; vezelbreedte: 2mm
Type - Graphics - Coarse Scale Fill Color: 0; Coarse Scale Fill Pattern: Solid fill
Type - Identity Data - Type Image: Raster image: Heraklith Basispaneel.jpg; Assembly Code: 42.10; Assembly Description: binnenwandafwerkingen; algemeen (verzamelniveau); brandweerstand: n.v.t; Description: Basispaneel - 50mm; DoP: W4302APCPR; email: customerservice.nl@knaufinsulation.com; geluidsabsorbtie: 0,65; Manufacturer: Knauf Insulation B.V. Knauf Insulation B.V.; Model: Heraklith® | Basispaneel is een houtwolcementpaneel; NLRS_C_Code_Brandklasse: B-s1,d0; NLRS_C_content_creator: Cadix; NLRS_C_content_versie: V1.0; phone: +31(0)162-421245; product URL: https://heraklith.nl/houtwol-producten/heraklith-basis; Type Name: NLRS_42_WA_Heraklith - Basis 50x2000x600mm; URL: www.heraklith.nl; warmteweerstand: 0,60 (m2.K/W)
Type - Other - Category: Walls; Family Name: Basic Wall
Classification: 42.10 binnenwandafwerkingen; algemeen (verzamelniveau) (Uniformat)
BaseQuantities - Height: 1800 mm; Length: 2000 mm; Width: 50 mm; GrossFootprintArea: 0.1 m2; GrossSideArea: 3.6 m2; GrossVolume: 0.18 m3
Constraints - Room Bounding: yes; Base Constraint: Level: 00 begane grond; Base Extension Distance: 0 mm; Base is Attached: no; Base Offset: 0 mm; Location Line: Wall Centerline; Related to Mass: no; Top Constraint: Level: 01 eerste verdieping; Top Extension Distance: 0 mm; Top is Attached: no; Top Offset: 0 mm; Unconnected Height: 1800 mm
Dimensions - Area: 3.6 m2; Length: 2000 mm; Volume: 0.18 m3
Other - Family: Basic Wall: NLRS_42_WA_Heraklith - Basis 50x2000x600mm; Family and Type: Basic Wall: NLRS_42_WA_Heraklith - Basis 50x2000x600mm; Type: Basic Wall: NLRS_42_WA_Heraklith - Basis 50x2000x600mm; Type Id: Basic Wall: NLRS_42_WA_Heraklith - Basis 50x2000x600mm
Phasing - Phase Created: 1
Structural - Enable Analytical Model: no; Structural: no; Structural Usage: Non-bearing
Pset_WallCommon - LoadBearing: no; ExtendToStructure: no; IsExternal: no; Reference: NLRS_42_WA_Heraklith - Basis 50x2000x600mm; ThermalTransmittance: 1.6 kg/K/s3
Pset_ManufacturerTypeInformation - Manufacturer: Knauf Insulation B.V. Knauf Insulation B.V.
